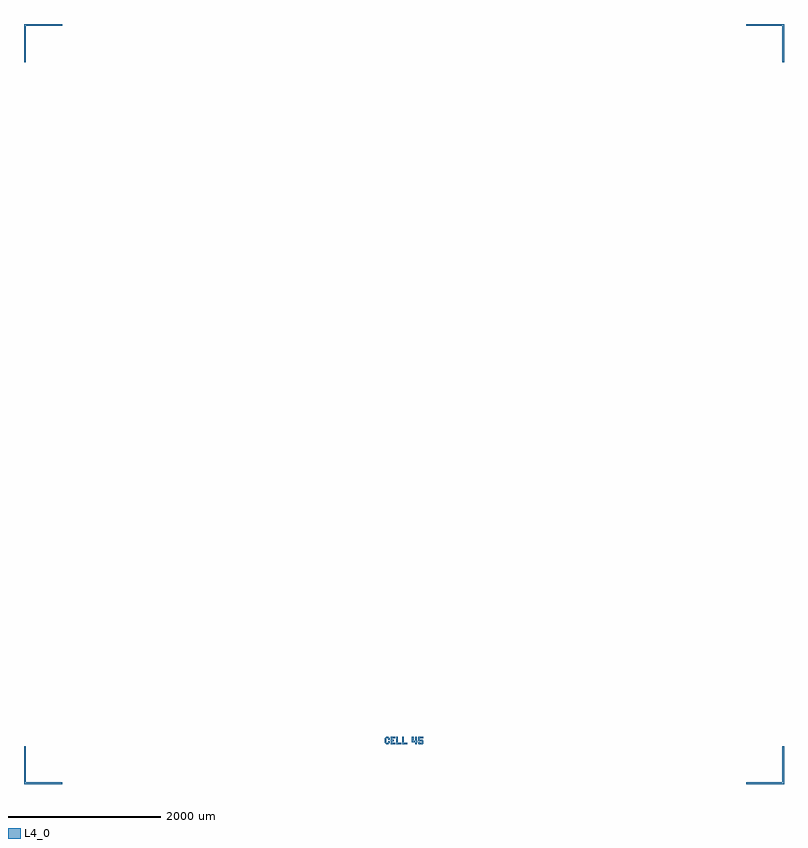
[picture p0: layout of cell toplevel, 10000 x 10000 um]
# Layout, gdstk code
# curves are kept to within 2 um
import gdstk
lib = gdstk.Library(unit=1e-6, precision=1e-09)
def P(c, l, *ps):  # polygons
    for p in ps: c.add(gdstk.Polygon(p, *l))
L4_0 = (4, 0)

toplevel = lib.new_cell('toplevel')
P(toplevel, L4_0, [(5000,5000),(5000,4500),(4980,4500),(4980,4980),(4500,4980),(4500,5000)],
  [(-5000,5000),(-5000,4500),(-4980,4500),(-4980,4980),(-4500,4980),(-4500,5000)],
  [(5000,-5000),(5000,-4500),(4980,-4500),(4980,-4980),(4500,-4980),(4500,-5000)],
  [(-5000,-5000),(-5000,-4500),(-4980,-4500),(-4980,-4980),(-4500,-4980),(-4500,-5000)],
  [(-235,-4480),(-255,-4460),(-255,-4400),(-235,-4380),(-205,-4380),(-185,-4400),(-185,-4420),(-205,-4420),(-205,-4410),(-215,-4400),(-225,-4400),(-235,-4410),(-235,-4450),(-225,-4460),(-215,-4460),(-205,-4450),(-205,-4440),(-185,-4440),(-185,-4460),(-205,-4480)],
  [(-115,-4380),(-115,-4400),(-155,-4400),(-155,-4420),(-135,-4420),(-135,-4440),(-155,-4440),(-155,-4460),(-115,-4460),(-115,-4480),(-175,-4480),(-175,-4380),(-115,-4380)],
  [(-105,-4380),(-85,-4380),(-85,-4460),(-35,-4460),(-35,-4480),(-105,-4480),(-105,-4380)],
  [(-25,-4380),(-5,-4380),(-5,-4460),(45,-4460),(45,-4480),(-25,-4480),(-25,-4380)],
  [(175,-4430),(175,-4450),(165,-4450),(165,-4480),(145,-4480),(145,-4450),(105,-4450),(105,-4380),(125,-4380),(125,-4430),(145,-4430),(145,-4380),(165,-4380),(165,-4430),(175,-4430)],
  [(255,-4400),(205,-4400),(205,-4420),(245,-4420),(255,-4430),(255,-4470),(245,-4480),(195,-4480),(185,-4470),(185,-4450),(205,-4450),(205,-4460),(235,-4460),(235,-4440),(195,-4440),(185,-4430),(185,-4380),(255,-4380)])

lib.write_gds('toplevel.gds')
